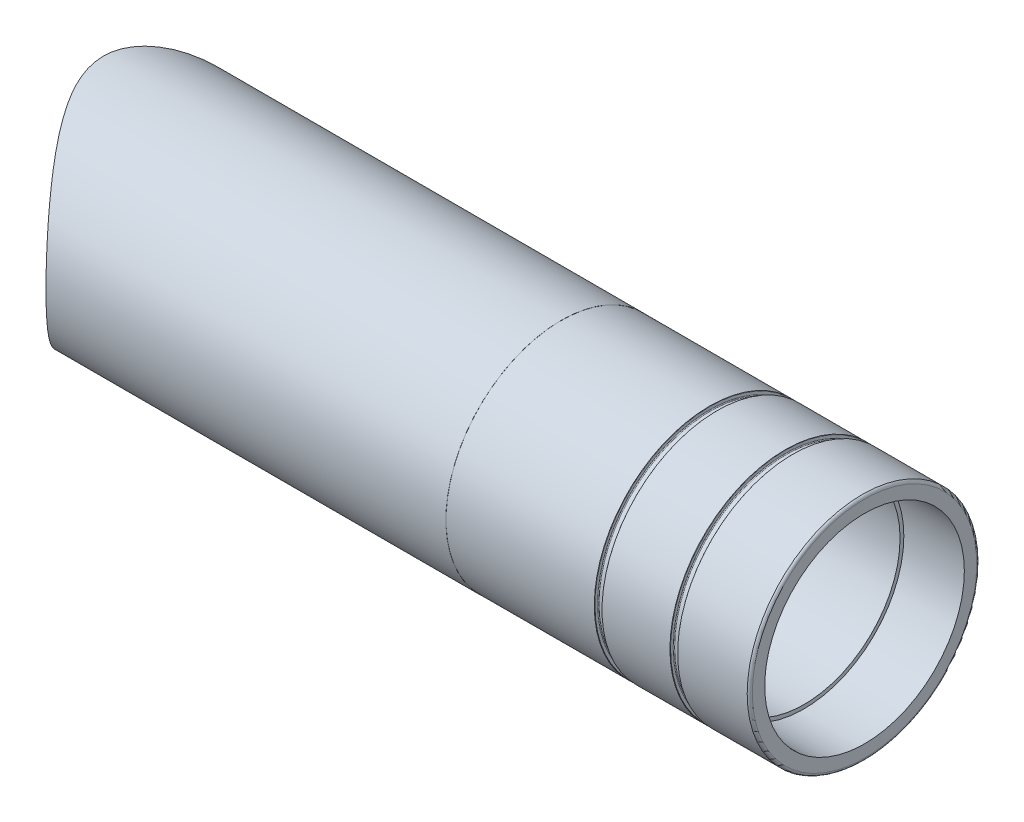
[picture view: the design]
ISO-10303-21;
HEADER;
FILE_DESCRIPTION(('STEP AP214'),'2;1');
FILE_NAME('part.step','',(''),(''),'','','');
FILE_SCHEMA(('AUTOMOTIVE_DESIGN { 1 0 10303 214 1 1 1 1 }'));
ENDSEC;
DATA;
#1=APPLICATION_CONTEXT('core data for automotive mechanical design processes');
#2=APPLICATION_PROTOCOL_DEFINITION('international standard','automotive_design',2000,#1);
#3=PRODUCT_CONTEXT('',#1,'mechanical');
#4=PRODUCT('Part','Part','',(#3));
#5=PRODUCT_RELATED_PRODUCT_CATEGORY('part','',(#4));
#6=PRODUCT_DEFINITION_FORMATION('','',#4);
#7=PRODUCT_DEFINITION_CONTEXT('part definition',#1,'design');
#8=PRODUCT_DEFINITION('design','',#6,#7);
#9=PRODUCT_DEFINITION_SHAPE('','',#8);
#10=(LENGTH_UNIT() NAMED_UNIT(*) SI_UNIT(.MILLI.,.METRE.));
#11=(NAMED_UNIT(*) PLANE_ANGLE_UNIT() SI_UNIT($,.RADIAN.));
#12=(NAMED_UNIT(*) SI_UNIT($,.STERADIAN.) SOLID_ANGLE_UNIT());
#13=UNCERTAINTY_MEASURE_WITH_UNIT(LENGTH_MEASURE(1.E-05),#10,'distance_accuracy_value','');
#14=(GEOMETRIC_REPRESENTATION_CONTEXT(3) GLOBAL_UNCERTAINTY_ASSIGNED_CONTEXT((#13)) GLOBAL_UNIT_ASSIGNED_CONTEXT((#10,
#11,#12)) REPRESENTATION_CONTEXT('',''));
#15=CARTESIAN_POINT('',(0.,0.,0.));
#16=DIRECTION('',(0.,0.,1.));
#17=DIRECTION('',(1.,0.,0.));
#18=AXIS2_PLACEMENT_3D('',#15,#16,#17);
#19=CARTESIAN_POINT('',(130.,0.,0.));
#20=DIRECTION('',(-1.,0.,0.));
#21=DIRECTION('',(0.,0.,1.));
#22=AXIS2_PLACEMENT_3D('',#19,#20,#21);
#23=CYLINDRICAL_SURFACE('',#22,38.1);
#24=CARTESIAN_POINT('',(-121.633822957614,38.1,0.));
#25=CARTESIAN_POINT('',(-121.633806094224,38.0999929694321,0.712902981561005));
#26=CARTESIAN_POINT('',(-121.606812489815,38.0799361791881,1.42607195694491));
#27=CARTESIAN_POINT('',(-121.500174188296,38.0001862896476,2.84651109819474));
#28=CARTESIAN_POINT('',(-121.420493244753,37.9404659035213,3.55377686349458));
#29=CARTESIAN_POINT('',(-121.212067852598,37.7825619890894,4.95874631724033));
#30=CARTESIAN_POINT('',(-121.083181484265,37.6842671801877,5.65641624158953));
#31=CARTESIAN_POINT('',(-120.782014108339,37.4512405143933,7.03592331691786));
#32=CARTESIAN_POINT('',(-120.609733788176,37.316509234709,7.71776071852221));
#33=CARTESIAN_POINT('',(-120.161172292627,36.9594738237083,9.29919618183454));
#34=CARTESIAN_POINT('',(-119.869608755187,36.7230293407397,10.1912740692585));
#35=CARTESIAN_POINT('',(-119.234485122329,36.1925973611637,11.9390531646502));
#36=CARTESIAN_POINT('',(-118.890901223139,35.8985835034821,12.7947374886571));
#37=CARTESIAN_POINT('',(-118.164909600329,35.2563815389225,14.4708260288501));
#38=CARTESIAN_POINT('',(-117.782415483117,34.9080719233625,15.2911457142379));
#39=CARTESIAN_POINT('',(-116.991025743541,34.1607056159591,16.8949377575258));
#40=CARTESIAN_POINT('',(-116.582130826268,33.7616502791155,17.678411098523));
#41=CARTESIAN_POINT('',(-115.879872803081,33.0489348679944,18.9666786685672));
#42=CARTESIAN_POINT('',(-115.590934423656,32.7482571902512,19.4811461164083));
#43=CARTESIAN_POINT('',(-115.007908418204,32.1245366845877,20.4933534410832));
#44=CARTESIAN_POINT('',(-114.713820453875,31.80149238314,20.9910922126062));
#45=CARTESIAN_POINT('',(-113.827347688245,30.7990943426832,22.4595525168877));
#46=CARTESIAN_POINT('',(-113.230812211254,30.0865336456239,23.4054131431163));
#47=CARTESIAN_POINT('',(-112.044403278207,28.5752646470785,25.2282523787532));
#48=CARTESIAN_POINT('',(-111.454524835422,27.7766263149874,26.105285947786));
#49=CARTESIAN_POINT('',(-110.295797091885,26.0934756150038,27.7876831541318));
#50=CARTESIAN_POINT('',(-109.726940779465,25.2089922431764,28.5930708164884));
#51=CARTESIAN_POINT('',(-108.733664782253,23.5390612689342,29.9741920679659));
#52=CARTESIAN_POINT('',(-108.302977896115,22.7687723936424,30.5637897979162));
#53=CARTESIAN_POINT('',(-107.471226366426,21.1745471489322,31.6891191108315));
#54=CARTESIAN_POINT('',(-107.070160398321,20.3506131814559,32.2248531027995));
#55=CARTESIAN_POINT('',(-106.305395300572,18.6520232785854,33.2368483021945));
#56=CARTESIAN_POINT('',(-105.941649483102,17.7774329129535,33.7131839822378));
#57=CARTESIAN_POINT('',(-105.25824077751,15.9796479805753,34.6015251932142));
#58=CARTESIAN_POINT('',(-104.938570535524,15.0564615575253,35.0135414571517));
#59=CARTESIAN_POINT('',(-104.398197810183,13.3196580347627,35.7060673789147));
#60=CARTESIAN_POINT('',(-104.169853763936,12.5125906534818,35.9970673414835));
#61=CARTESIAN_POINT('',(-103.753034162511,10.8712805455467,36.5262707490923));
#62=CARTESIAN_POINT('',(-103.564554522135,10.0370406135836,36.7644796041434));
#63=CARTESIAN_POINT('',(-103.231088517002,8.34631717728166,37.1847743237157));
#64=CARTESIAN_POINT('',(-103.086085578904,7.48984228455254,37.3668815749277));
#65=CARTESIAN_POINT('',(-102.842431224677,5.7599142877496,37.6723345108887));
#66=CARTESIAN_POINT('',(-102.743780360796,4.88646098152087,37.7956794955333));
#67=CARTESIAN_POINT('',(-102.594702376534,3.12585197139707,37.9819085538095));
#68=CARTESIAN_POINT('',(-102.544447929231,2.23865859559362,38.0445761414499));
#69=CARTESIAN_POINT('',(-102.493907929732,0.460626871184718,38.107599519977));
#70=CARTESIAN_POINT('',(-102.493622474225,-0.43021148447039,38.1079551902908));
#71=CARTESIAN_POINT('',(-102.543026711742,-2.20834915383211,38.0463486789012));
#72=CARTESIAN_POINT('',(-102.592717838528,-3.09564836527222,37.9843847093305));
#73=CARTESIAN_POINT('',(-102.740957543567,-4.85966327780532,37.7992086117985));
#74=CARTESIAN_POINT('',(-102.839504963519,-5.73637922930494,37.6759979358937));
#75=CARTESIAN_POINT('',(-103.07654079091,-7.424619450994,37.3788518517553));
#76=CARTESIAN_POINT('',(-103.21251360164,-8.23706430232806,37.2081052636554));
#77=CARTESIAN_POINT('',(-103.523617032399,-9.8419475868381,36.8161429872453));
#78=CARTESIAN_POINT('',(-103.698745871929,-10.6343869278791,36.5949295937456));
#79=CARTESIAN_POINT('',(-104.085189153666,-12.1953603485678,36.1047446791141));
#80=CARTESIAN_POINT('',(-104.296508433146,-12.963891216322,35.8357667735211));
#81=CARTESIAN_POINT('',(-104.751982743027,-14.4737297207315,35.2530295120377));
#82=CARTESIAN_POINT('',(-104.9961397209,-15.2150357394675,34.9392675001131));
#83=CARTESIAN_POINT('',(-105.538532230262,-16.7374369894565,34.2379349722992));
#84=CARTESIAN_POINT('',(-105.839706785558,-17.5155533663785,33.8461749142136));
#85=CARTESIAN_POINT('',(-106.472482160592,-19.0336982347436,33.0163123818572));
#86=CARTESIAN_POINT('',(-106.804084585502,-19.7737247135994,32.578207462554));
#87=CARTESIAN_POINT('',(-107.493074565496,-21.2143597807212,31.6589852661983));
#88=CARTESIAN_POINT('',(-107.850471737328,-21.9149534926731,31.1778519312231));
#89=CARTESIAN_POINT('',(-108.586206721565,-23.2754358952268,30.1757845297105));
#90=CARTESIAN_POINT('',(-108.964545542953,-23.9353226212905,29.6548485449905));
#91=CARTESIAN_POINT('',(-109.817239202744,-25.3457609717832,28.4643791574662));
#92=CARTESIAN_POINT('',(-110.295298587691,-26.0869274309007,27.7863627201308));
#93=CARTESIAN_POINT('',(-111.266756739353,-27.5086771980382,26.3795967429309));
#94=CARTESIAN_POINT('',(-111.760158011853,-28.1892505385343,25.6508388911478));
#95=CARTESIAN_POINT('',(-112.754109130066,-29.4900710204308,24.1440992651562));
#96=CARTESIAN_POINT('',(-113.254666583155,-30.110247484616,23.3660615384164));
#97=CARTESIAN_POINT('',(-114.252783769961,-31.2886958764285,21.762751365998));
#98=CARTESIAN_POINT('',(-114.750343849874,-31.8469750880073,20.9374844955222));
#99=CARTESIAN_POINT('',(-115.687077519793,-32.8527304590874,19.3166619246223));
#100=CARTESIAN_POINT('',(-116.127456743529,-33.3056628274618,18.5251885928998));
#101=CARTESIAN_POINT('',(-116.986986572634,-34.1578258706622,16.9024516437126));
#102=CARTESIAN_POINT('',(-117.40613444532,-34.5570496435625,16.071182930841));
#103=CARTESIAN_POINT('',(-118.210728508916,-35.2985991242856,14.3693876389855));
#104=CARTESIAN_POINT('',(-118.596220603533,-35.641002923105,13.4989170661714));
#105=CARTESIAN_POINT('',(-119.31969284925,-36.2656462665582,11.7176212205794));
#106=CARTESIAN_POINT('',(-119.657696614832,-36.5479157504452,10.8068163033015));
#107=CARTESIAN_POINT('',(-120.179430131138,-36.9737950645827,9.22012161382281));
#108=CARTESIAN_POINT('',(-120.379297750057,-37.1337707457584,8.55391338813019));
#109=CARTESIAN_POINT('',(-120.74063606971,-37.4191487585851,7.20369408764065));
#110=CARTESIAN_POINT('',(-120.902105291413,-37.5445497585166,6.51968232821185));
#111=CARTESIAN_POINT('',(-121.179950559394,-37.7582506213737,5.13914523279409));
#112=CARTESIAN_POINT('',(-121.296471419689,-37.8466697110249,4.44266777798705));
#113=CARTESIAN_POINT('',(-121.479882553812,-37.9850804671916,3.03968919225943));
#114=CARTESIAN_POINT('',(-121.546807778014,-38.0350991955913,2.33319547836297));
#115=CARTESIAN_POINT('',(-121.602801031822,-38.0768870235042,1.35427329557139));
#116=CARTESIAN_POINT('',(-121.614421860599,-38.0855491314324,1.0836525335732));
#117=CARTESIAN_POINT('',(-121.629936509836,-38.0971073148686,0.542034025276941));
#118=CARTESIAN_POINT('',(-121.63382936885,-38.1000026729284,0.271036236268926));
#119=CARTESIAN_POINT('',(-121.633806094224,-38.0999929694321,-0.712902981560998));
#120=CARTESIAN_POINT('',(-121.606812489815,-38.0799361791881,-1.4260719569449));
#121=CARTESIAN_POINT('',(-121.500174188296,-38.0001862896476,-2.84651109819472));
#122=CARTESIAN_POINT('',(-121.420493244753,-37.9404659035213,-3.55377686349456));
#123=CARTESIAN_POINT('',(-121.212067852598,-37.7825619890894,-4.95874631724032));
#124=CARTESIAN_POINT('',(-121.083181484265,-37.6842671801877,-5.65641624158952));
#125=CARTESIAN_POINT('',(-120.782014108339,-37.4512405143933,-7.03592331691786));
#126=CARTESIAN_POINT('',(-120.609733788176,-37.316509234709,-7.7177607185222));
#127=CARTESIAN_POINT('',(-120.161172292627,-36.9594738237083,-9.29919618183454));
#128=CARTESIAN_POINT('',(-119.869608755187,-36.7230293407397,-10.1912740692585));
#129=CARTESIAN_POINT('',(-119.234485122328,-36.1925973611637,-11.9390531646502));
#130=CARTESIAN_POINT('',(-118.890901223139,-35.8985835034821,-12.7947374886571));
#131=CARTESIAN_POINT('',(-118.164909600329,-35.2563815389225,-14.4708260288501));
#132=CARTESIAN_POINT('',(-117.782415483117,-34.9080719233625,-15.2911457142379));
#133=CARTESIAN_POINT('',(-116.991025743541,-34.1607056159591,-16.8949377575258));
#134=CARTESIAN_POINT('',(-116.582130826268,-33.7616502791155,-17.678411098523));
#135=CARTESIAN_POINT('',(-115.879872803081,-33.0489348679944,-18.9666786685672));
#136=CARTESIAN_POINT('',(-115.590934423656,-32.7482571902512,-19.4811461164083));
#137=CARTESIAN_POINT('',(-115.007908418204,-32.1245366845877,-20.4933534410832));
#138=CARTESIAN_POINT('',(-114.713820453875,-31.80149238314,-20.9910922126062));
#139=CARTESIAN_POINT('',(-113.827347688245,-30.7990943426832,-22.4595525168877));
#140=CARTESIAN_POINT('',(-113.230812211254,-30.0865336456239,-23.4054131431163));
#141=CARTESIAN_POINT('',(-112.044403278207,-28.5752646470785,-25.2282523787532));
#142=CARTESIAN_POINT('',(-111.454524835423,-27.7766263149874,-26.105285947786));
#143=CARTESIAN_POINT('',(-110.295797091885,-26.0934756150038,-27.7876831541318));
#144=CARTESIAN_POINT('',(-109.726940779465,-25.2089922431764,-28.5930708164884));
#145=CARTESIAN_POINT('',(-108.733664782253,-23.5390612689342,-29.9741920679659));
#146=CARTESIAN_POINT('',(-108.302977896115,-22.7687723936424,-30.5637897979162));
#147=CARTESIAN_POINT('',(-107.471226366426,-21.1745471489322,-31.6891191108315));
#148=CARTESIAN_POINT('',(-107.070160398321,-20.3506131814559,-32.2248531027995));
#149=CARTESIAN_POINT('',(-106.305395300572,-18.6520232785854,-33.2368483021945));
#150=CARTESIAN_POINT('',(-105.941649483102,-17.7774329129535,-33.7131839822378));
#151=CARTESIAN_POINT('',(-105.25824077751,-15.9796479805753,-34.6015251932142));
#152=CARTESIAN_POINT('',(-104.938570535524,-15.0564615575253,-35.0135414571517));
#153=CARTESIAN_POINT('',(-104.398197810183,-13.3196580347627,-35.7060673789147));
#154=CARTESIAN_POINT('',(-104.169853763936,-12.5125906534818,-35.9970673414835));
#155=CARTESIAN_POINT('',(-103.753034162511,-10.8712805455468,-36.5262707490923));
#156=CARTESIAN_POINT('',(-103.564554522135,-10.0370406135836,-36.7644796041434));
#157=CARTESIAN_POINT('',(-103.231088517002,-8.34631717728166,-37.1847743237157));
#158=CARTESIAN_POINT('',(-103.086085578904,-7.48984228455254,-37.3668815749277));
#159=CARTESIAN_POINT('',(-102.842431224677,-5.7599142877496,-37.6723345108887));
#160=CARTESIAN_POINT('',(-102.743780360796,-4.88646098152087,-37.7956794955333));
#161=CARTESIAN_POINT('',(-102.594702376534,-3.12585197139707,-37.9819085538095));
#162=CARTESIAN_POINT('',(-102.544447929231,-2.23865859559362,-38.0445761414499));
#163=CARTESIAN_POINT('',(-102.493907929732,-0.460626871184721,-38.107599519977));
#164=CARTESIAN_POINT('',(-102.493622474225,0.430211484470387,-38.1079551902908));
#165=CARTESIAN_POINT('',(-102.543026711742,2.20834915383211,-38.0463486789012));
#166=CARTESIAN_POINT('',(-102.592717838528,3.09564836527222,-37.9843847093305));
#167=CARTESIAN_POINT('',(-102.740957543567,4.85966327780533,-37.7992086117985));
#168=CARTESIAN_POINT('',(-102.839504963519,5.73637922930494,-37.6759979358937));
#169=CARTESIAN_POINT('',(-103.07654079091,7.42461945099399,-37.3788518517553));
#170=CARTESIAN_POINT('',(-103.21251360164,8.23706430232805,-37.2081052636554));
#171=CARTESIAN_POINT('',(-103.523617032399,9.84194758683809,-36.8161429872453));
#172=CARTESIAN_POINT('',(-103.698745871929,10.6343869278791,-36.5949295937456));
#173=CARTESIAN_POINT('',(-104.085189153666,12.1953603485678,-36.1047446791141));
#174=CARTESIAN_POINT('',(-104.296508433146,12.963891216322,-35.8357667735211));
#175=CARTESIAN_POINT('',(-104.751982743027,14.4737297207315,-35.2530295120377));
#176=CARTESIAN_POINT('',(-104.9961397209,15.2150357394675,-34.9392675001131));
#177=CARTESIAN_POINT('',(-105.538532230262,16.7374369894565,-34.2379349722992));
#178=CARTESIAN_POINT('',(-105.839706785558,17.5155533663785,-33.8461749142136));
#179=CARTESIAN_POINT('',(-106.472482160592,19.0336982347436,-33.0163123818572));
#180=CARTESIAN_POINT('',(-106.804084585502,19.7737247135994,-32.578207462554));
#181=CARTESIAN_POINT('',(-107.493074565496,21.2143597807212,-31.6589852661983));
#182=CARTESIAN_POINT('',(-107.850471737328,21.9149534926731,-31.177851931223));
#183=CARTESIAN_POINT('',(-108.586206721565,23.2754358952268,-30.1757845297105));
#184=CARTESIAN_POINT('',(-108.964545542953,23.9353226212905,-29.6548485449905));
#185=CARTESIAN_POINT('',(-109.817239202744,25.3457609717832,-28.4643791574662));
#186=CARTESIAN_POINT('',(-110.295298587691,26.0869274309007,-27.7863627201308));
#187=CARTESIAN_POINT('',(-111.266756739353,27.5086771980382,-26.3795967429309));
#188=CARTESIAN_POINT('',(-111.760158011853,28.1892505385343,-25.6508388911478));
#189=CARTESIAN_POINT('',(-112.754109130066,29.4900710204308,-24.1440992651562));
#190=CARTESIAN_POINT('',(-113.254666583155,30.110247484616,-23.3660615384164));
#191=CARTESIAN_POINT('',(-114.252783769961,31.2886958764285,-21.762751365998));
#192=CARTESIAN_POINT('',(-114.750343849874,31.8469750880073,-20.9374844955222));
#193=CARTESIAN_POINT('',(-115.687077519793,32.8527304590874,-19.3166619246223));
#194=CARTESIAN_POINT('',(-116.127456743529,33.3056628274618,-18.5251885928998));
#195=CARTESIAN_POINT('',(-116.986986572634,34.1578258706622,-16.9024516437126));
#196=CARTESIAN_POINT('',(-117.40613444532,34.5570496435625,-16.071182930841));
#197=CARTESIAN_POINT('',(-118.210728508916,35.2985991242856,-14.3693876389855));
#198=CARTESIAN_POINT('',(-118.596220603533,35.641002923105,-13.4989170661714));
#199=CARTESIAN_POINT('',(-119.31969284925,36.2656462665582,-11.7176212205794));
#200=CARTESIAN_POINT('',(-119.657696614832,36.5479157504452,-10.8068163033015));
#201=CARTESIAN_POINT('',(-120.179430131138,36.9737950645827,-9.22012161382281));
#202=CARTESIAN_POINT('',(-120.379297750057,37.1337707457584,-8.55391338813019));
#203=CARTESIAN_POINT('',(-120.74063606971,37.4191487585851,-7.20369408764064));
#204=CARTESIAN_POINT('',(-120.902105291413,37.5445497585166,-6.51968232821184));
#205=CARTESIAN_POINT('',(-121.179950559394,37.7582506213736,-5.13914523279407));
#206=CARTESIAN_POINT('',(-121.296471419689,37.8466697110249,-4.44266777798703));
#207=CARTESIAN_POINT('',(-121.479882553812,37.9850804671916,-3.03968919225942));
#208=CARTESIAN_POINT('',(-121.546807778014,38.0350991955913,-2.33319547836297));
#209=CARTESIAN_POINT('',(-121.602801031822,38.0768870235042,-1.35427329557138));
#210=CARTESIAN_POINT('',(-121.614421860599,38.0855491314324,-1.08365253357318));
#211=CARTESIAN_POINT('',(-121.629936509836,38.0971073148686,-0.542034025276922));
#212=CARTESIAN_POINT('',(-121.63382936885,38.1000026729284,-0.271036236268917));
#213=CARTESIAN_POINT('',(-121.633822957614,38.1,0.));
#214=B_SPLINE_CURVE_WITH_KNOTS('',3,(#24,#25,#26,#27,#28,#29,#30,#31,#32,#33,#34,#35,#36,#37,
#38,#39,#40,#41,#42,#43,#44,#45,#46,#47,#48,#49,#50,#51,#52,#53,#54,#55,#56,#57,#58,#59,#60,#61,
#62,#63,#64,#65,#66,#67,#68,#69,#70,#71,#72,#73,#74,#75,#76,#77,#78,#79,#80,#81,#82,#83,#84,#85,
#86,#87,#88,#89,#90,#91,#92,#93,#94,#95,#96,#97,#98,#99,#100,#101,#102,#103,#104,#105,#106,#107,
#108,#109,#110,#111,#112,#113,#114,#115,#116,#117,#118,#119,#120,#121,#122,#123,#124,#125,#126,
#127,#128,#129,#130,#131,#132,#133,#134,#135,#136,#137,#138,#139,#140,#141,#142,#143,#144,#145,
#146,#147,#148,#149,#150,#151,#152,#153,#154,#155,#156,#157,#158,#159,#160,#161,#162,#163,#164,
#165,#166,#167,#168,#169,#170,#171,#172,#173,#174,#175,#176,#177,#178,#179,#180,#181,#182,#183,
#184,#185,#186,#187,#188,#189,#190,#191,#192,#193,#194,#195,#196,#197,#198,#199,#200,#201,#202,
#203,#204,#205,#206,#207,#208,#209,#210,#211,#212,#213),.UNSPECIFIED.,.T.,.F.,(4,2,2,2,2,2,2,2,
2,2,2,2,2,2,2,2,2,2,2,2,2,2,2,2,2,2,2,2,2,2,2,2,2,2,2,2,2,2,2,2,2,2,2,2,2,2,2,2,2,2,2,2,2,2,2,2,
2,2,2,2,2,2,2,2,2,2,2,2,2,2,2,2,2,2,2,2,2,2,2,2,2,2,2,2,2,2,2,2,2,2,2,2,2,2,4),(0.,
2.13839611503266,4.27826487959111,6.42435272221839,8.57040656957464,11.4693230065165,
14.3695699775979,17.2764031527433,20.1831587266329,22.1693054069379,24.1555830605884,
28.1285370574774,32.0982855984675,36.0666979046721,39.2479049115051,42.4289695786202,
45.6060048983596,48.7825094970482,51.443218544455,54.1036547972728,56.7630755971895,
59.4225280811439,62.091434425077,64.7603459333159,67.4293340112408,70.0982588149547,
72.6193037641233,75.1402340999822,77.6615016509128,80.1829187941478,82.9455722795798,
85.7083715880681,88.4722062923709,91.2361742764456,94.5704212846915,97.9052157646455,
101.243866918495,104.582124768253,107.617933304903,110.654131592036,113.686121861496,
116.716599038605,118.855911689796,120.995306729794,123.127750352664,125.258689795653,
126.071578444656,126.884568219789,129.022964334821,131.16283309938,133.308920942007,
135.454974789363,138.353891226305,141.254138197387,144.160971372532,147.067726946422,
149.053873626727,151.040151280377,155.013105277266,158.982853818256,162.951266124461,
166.132473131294,169.313537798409,172.490573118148,175.667077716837,178.327786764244,
180.988223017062,183.647643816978,186.307096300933,188.976002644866,191.644914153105,
194.313902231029,196.982827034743,199.503871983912,202.024802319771,204.546069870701,
207.067487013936,209.830140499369,212.592939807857,215.35677451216,218.120742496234,
221.45498950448,224.789783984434,228.128435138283,231.466692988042,234.502501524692,
237.538699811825,240.570690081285,243.601167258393,245.740479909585,247.879874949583,
250.012318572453,252.143258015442,252.956146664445,253.769136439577),.UNSPECIFIED.);
#215=CARTESIAN_POINT('',(-121.633822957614,38.1,0.));
#216=VERTEX_POINT('',#215);
#217=EDGE_CURVE('E116',#216,#216,#214,.T.);
#218=ORIENTED_EDGE('',*,*,#217,.T.);
#219=EDGE_LOOP('',(#218));
#220=FACE_BOUND('',#219,.T.);
#221=CARTESIAN_POINT('',(29.7,0.,0.));
#222=DIRECTION('',(1.,0.,0.));
#223=DIRECTION('',(0.,0.,-1.));
#224=AXIS2_PLACEMENT_3D('',#221,#222,#223);
#225=CIRCLE('',#224,38.1);
#226=CARTESIAN_POINT('',(29.7,0.,-38.1));
#227=VERTEX_POINT('',#226);
#228=EDGE_CURVE('E35',#227,#227,#225,.T.);
#229=ORIENTED_EDGE('',*,*,#228,.F.);
#230=EDGE_LOOP('',(#229));
#231=FACE_BOUND('',#230,.T.);
#232=ADVANCED_FACE('F31',(#220,#231),#23,.T.);
#233=CARTESIAN_POINT('',(129.,0.,0.));
#234=DIRECTION('',(1.,0.,0.));
#235=DIRECTION('',(0.,0.,-1.));
#236=AXIS2_PLACEMENT_3D('',#233,#234,#235);
#237=TOROIDAL_SURFACE('',#236,37.1,1.);
#238=CARTESIAN_POINT('',(130.,0.,0.));
#239=DIRECTION('',(1.,0.,0.));
#240=DIRECTION('',(0.,0.,-1.));
#241=AXIS2_PLACEMENT_3D('',#238,#239,#240);
#242=CIRCLE('',#241,37.1);
#243=CARTESIAN_POINT('',(130.,0.,-37.1));
#244=VERTEX_POINT('',#243);
#245=EDGE_CURVE('E122',#244,#244,#242,.T.);
#246=ORIENTED_EDGE('',*,*,#245,.F.);
#247=EDGE_LOOP('',(#246));
#248=FACE_BOUND('',#247,.T.);
#249=CARTESIAN_POINT('',(129.274804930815,0.,0.));
#250=DIRECTION('',(-1.,0.,0.));
#251=DIRECTION('',(0.,0.,1.));
#252=AXIS2_PLACEMENT_3D('',#249,#250,#251);
#253=CIRCLE('',#252,38.0615);
#254=CARTESIAN_POINT('',(129.274804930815,0.,38.0615));
#255=VERTEX_POINT('',#254);
#256=EDGE_CURVE('E144',#255,#255,#253,.F.);
#257=ORIENTED_EDGE('',*,*,#256,.T.);
#258=EDGE_LOOP('',(#257));
#259=FACE_BOUND('',#258,.T.);
#260=ADVANCED_FACE('F207',(#248,#259),#237,.T.);
#261=CARTESIAN_POINT('',(130.,0.,0.));
#262=DIRECTION('',(-1.,0.,0.));
#263=DIRECTION('',(0.,0.,1.));
#264=AXIS2_PLACEMENT_3D('',#261,#262,#263);
#265=CYLINDRICAL_SURFACE('',#264,31.75);
#266=CARTESIAN_POINT('',(-80.,0.,0.));
#267=DIRECTION('',(1.,0.,0.));
#268=DIRECTION('',(0.,0.,-1.));
#269=AXIS2_PLACEMENT_3D('',#266,#267,#268);
#270=CIRCLE('',#269,31.75);
#271=CARTESIAN_POINT('',(-80.,0.,-31.75));
#272=VERTEX_POINT('',#271);
#273=EDGE_CURVE('E55',#272,#272,#270,.T.);
#274=ORIENTED_EDGE('',*,*,#273,.F.);
#275=EDGE_LOOP('',(#274));
#276=FACE_BOUND('',#275,.T.);
#277=CARTESIAN_POINT('',(110.,0.,0.));
#278=DIRECTION('',(1.,0.,0.));
#279=DIRECTION('',(0.,0.,-1.));
#280=AXIS2_PLACEMENT_3D('',#277,#278,#279);
#281=CIRCLE('',#280,31.75);
#282=CARTESIAN_POINT('',(110.,0.,-31.75));
#283=VERTEX_POINT('',#282);
#284=EDGE_CURVE('E156',#283,#283,#281,.T.);
#285=ORIENTED_EDGE('',*,*,#284,.T.);
#286=EDGE_LOOP('',(#285));
#287=FACE_BOUND('',#286,.T.);
#288=ADVANCED_FACE('F204',(#276,#287),#265,.F.);
#289=CARTESIAN_POINT('',(-150.,0.,38.101));
#290=DIRECTION('',(0.,0.,-1.));
#291=DIRECTION('',(-1.,0.,0.));
#292=AXIS2_PLACEMENT_3D('',#289,#290,#291);
#293=CYLINDRICAL_SURFACE('',#292,47.5);
#294=ORIENTED_EDGE('',*,*,#217,.F.);
#295=EDGE_LOOP('',(#294));
#296=FACE_BOUND('',#295,.T.);
#297=CARTESIAN_POINT('',(-102.5,0.,33.));
#298=CARTESIAN_POINT('',(-102.49999794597,-0.821813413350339,33.0000022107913));
#299=CARTESIAN_POINT('',(-102.521371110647,-1.64360020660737,32.9692605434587));
#300=CARTESIAN_POINT('',(-102.606322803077,-3.2803756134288,32.8468048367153));
#301=CARTESIAN_POINT('',(-102.669899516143,-4.09536451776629,32.7550934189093));
#302=CARTESIAN_POINT('',(-102.837729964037,-5.71238311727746,32.5121118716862));
#303=CARTESIAN_POINT('',(-102.941996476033,-6.51440865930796,32.3608230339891));
#304=CARTESIAN_POINT('',(-103.188759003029,-8.09945233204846,32.0009285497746));
#305=CARTESIAN_POINT('',(-103.33125594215,-8.88247000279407,31.7923215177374));
#306=CARTESIAN_POINT('',(-103.65052470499,-10.4206614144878,31.3217746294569));
#307=CARTESIAN_POINT('',(-103.827123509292,-11.17595372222,31.0601036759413));
#308=CARTESIAN_POINT('',(-104.211418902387,-12.6586916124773,30.485892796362));
#309=CARTESIAN_POINT('',(-104.419115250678,-13.3861374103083,30.1733532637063));
#310=CARTESIAN_POINT('',(-104.861652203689,-14.8099766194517,29.5005870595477));
#311=CARTESIAN_POINT('',(-105.096492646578,-15.5063702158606,29.1403606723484));
#312=CARTESIAN_POINT('',(-105.589169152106,-16.8656700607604,28.3752981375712));
#313=CARTESIAN_POINT('',(-105.847006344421,-17.5285746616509,27.9704597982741));
#314=CARTESIAN_POINT('',(-106.404867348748,-18.8756844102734,27.081647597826));
#315=CARTESIAN_POINT('',(-106.706607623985,-19.5566527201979,26.5938467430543));
#316=CARTESIAN_POINT('',(-107.326633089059,-20.8749722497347,25.5720779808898));
#317=CARTESIAN_POINT('',(-107.644919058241,-21.5123214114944,25.0381078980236));
#318=CARTESIAN_POINT('',(-108.292733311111,-22.7428671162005,23.9259430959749));
#319=CARTESIAN_POINT('',(-108.622276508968,-23.3360014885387,23.3476883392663));
#320=CARTESIAN_POINT('',(-109.286198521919,-24.4759376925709,22.1497673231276));
#321=CARTESIAN_POINT('',(-109.620577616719,-25.0227368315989,21.5300986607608));
#322=CARTESIAN_POINT('',(-110.345688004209,-26.1594166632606,20.1401268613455));
#323=CARTESIAN_POINT('',(-110.736143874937,-26.7403441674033,19.3623280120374));
#324=CARTESIAN_POINT('',(-111.503902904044,-27.8342806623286,17.7538453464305));
#325=CARTESIAN_POINT('',(-111.881202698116,-28.3472723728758,16.9231481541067));
#326=CARTESIAN_POINT('',(-112.60946561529,-29.3011519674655,15.2118665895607));
#327=CARTESIAN_POINT('',(-112.96046277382,-29.7421339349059,14.3313493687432));
#328=CARTESIAN_POINT('',(-113.622268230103,-30.5480361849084,12.5218699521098));
#329=CARTESIAN_POINT('',(-113.933097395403,-30.9129960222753,11.5929332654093));
#330=CARTESIAN_POINT('',(-114.411645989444,-31.4612104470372,9.98376961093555));
#331=CARTESIAN_POINT('',(-114.593952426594,-31.6658048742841,9.31509140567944));
#332=CARTESIAN_POINT('',(-114.926401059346,-32.0336411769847,7.95860457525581));
#333=CARTESIAN_POINT('',(-115.076548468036,-32.1968897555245,7.2707990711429));
#334=CARTESIAN_POINT('',(-115.339312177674,-32.4795939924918,5.88033972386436));
#335=CARTESIAN_POINT('',(-115.451990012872,-32.5991214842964,5.17771226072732));
#336=CARTESIAN_POINT('',(-115.635771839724,-32.7928002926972,3.76077566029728));
#337=CARTESIAN_POINT('',(-115.70687587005,-32.866951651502,3.04646653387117));
#338=CARTESIAN_POINT('',(-115.804736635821,-32.9687588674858,1.60748183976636));
#339=CARTESIAN_POINT('',(-115.831245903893,-32.9961552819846,0.882770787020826));
#340=CARTESIAN_POINT('',(-115.837943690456,-33.0030897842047,-0.567095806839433));
#341=CARTESIAN_POINT('',(-115.818132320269,-32.9826279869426,-1.29225134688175));
#342=CARTESIAN_POINT('',(-115.733069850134,-32.8942425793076,-2.73737948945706));
#343=CARTESIAN_POINT('',(-115.667791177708,-32.8262901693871,-3.45734867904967));
#344=CARTESIAN_POINT('',(-115.494614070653,-32.6442035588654,-4.88617881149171));
#345=CARTESIAN_POINT('',(-115.386714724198,-32.53006837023,-5.59503951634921));
#346=CARTESIAN_POINT('',(-115.140600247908,-32.2661212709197,-6.95309951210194));
#347=CARTESIAN_POINT('',(-115.004711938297,-32.1189970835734,-7.60325161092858));
#348=CARTESIAN_POINT('',(-114.703486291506,-31.7876739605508,-8.88727282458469));
#349=CARTESIAN_POINT('',(-114.538138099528,-31.6034613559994,-9.52113583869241));
#350=CARTESIAN_POINT('',(-114.182431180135,-31.1997452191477,-10.7706665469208));
#351=CARTESIAN_POINT('',(-113.992059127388,-30.9802228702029,-11.3863243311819));
#352=CARTESIAN_POINT('',(-113.590892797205,-30.5077527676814,-12.5976047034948));
#353=CARTESIAN_POINT('',(-113.380101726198,-30.2548102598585,-13.1932304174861));
#354=CARTESIAN_POINT('',(-112.828522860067,-29.5771639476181,-14.6679780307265));
#355=CARTESIAN_POINT('',(-112.47710340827,-29.1315079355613,-15.5335784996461));
#356=CARTESIAN_POINT('',(-111.750456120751,-28.170649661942,-17.2148983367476));
#357=CARTESIAN_POINT('',(-111.375218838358,-27.6554197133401,-18.0305976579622));
#358=CARTESIAN_POINT('',(-110.612353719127,-26.5576890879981,-19.6116503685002));
#359=CARTESIAN_POINT('',(-110.224705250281,-25.9750716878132,-20.3769126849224));
#360=CARTESIAN_POINT('',(-109.448475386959,-24.745753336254,-21.8533834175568));
#361=CARTESIAN_POINT('',(-109.059894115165,-24.0990604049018,-22.5645985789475));
#362=CARTESIAN_POINT('',(-108.287330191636,-22.7359558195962,-23.9378891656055));
#363=CARTESIAN_POINT('',(-107.903445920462,-22.0188522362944,-24.5993341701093));
#364=CARTESIAN_POINT('',(-107.154269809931,-20.5229900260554,-25.8604682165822));
#365=CARTESIAN_POINT('',(-106.788979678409,-19.7442257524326,-26.4601515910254));
#366=CARTESIAN_POINT('',(-106.08691732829,-18.1291247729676,-27.5917616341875));
#367=CARTESIAN_POINT('',(-105.750094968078,-17.2928942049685,-28.123808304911));
#368=CARTESIAN_POINT('',(-105.113288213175,-15.5653398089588,-29.1154829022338));
#369=CARTESIAN_POINT('',(-104.813292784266,-14.6740326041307,-29.5751325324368));
#370=CARTESIAN_POINT('',(-104.320219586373,-13.0446646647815,-30.3224765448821));
#371=CARTESIAN_POINT('',(-104.118179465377,-12.3164029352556,-30.625705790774));
#372=CARTESIAN_POINT('',(-103.745467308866,-10.8329472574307,-31.1813131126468));
#373=CARTESIAN_POINT('',(-103.574790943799,-10.077757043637,-31.43369820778));
#374=CARTESIAN_POINT('',(-103.26837063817,-8.54490271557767,-31.884518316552));
#375=CARTESIAN_POINT('',(-103.132609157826,-7.76725010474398,-32.0829804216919));
#376=CARTESIAN_POINT('',(-102.898872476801,-6.19403766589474,-32.4234723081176));
#377=CARTESIAN_POINT('',(-102.800898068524,-5.39847746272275,-32.5655009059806));
#378=CARTESIAN_POINT('',(-102.644703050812,-3.7920427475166,-32.7914753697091));
#379=CARTESIAN_POINT('',(-102.586639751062,-2.98112043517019,-32.8751914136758));
#380=CARTESIAN_POINT('',(-102.512295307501,-1.35337757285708,-32.9823224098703));
#381=CARTESIAN_POINT('',(-102.496014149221,-0.536557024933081,-33.0057373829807));
#382=CARTESIAN_POINT('',(-102.505634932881,1.09630954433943,-32.9918889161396));
#383=CARTESIAN_POINT('',(-102.531536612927,1.91235557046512,-32.9546258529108));
#384=CARTESIAN_POINT('',(-102.624886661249,3.53704383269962,-32.8200200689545));
#385=CARTESIAN_POINT('',(-102.692333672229,4.34568630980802,-32.7226793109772));
#386=CARTESIAN_POINT('',(-102.861708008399,5.89948023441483,-32.4773136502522));
#387=CARTESIAN_POINT('',(-102.961233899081,6.64545592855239,-32.3328117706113));
#388=CARTESIAN_POINT('',(-103.193362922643,8.12073187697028,-31.9941631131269));
#389=CARTESIAN_POINT('',(-103.325964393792,8.85003296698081,-31.8000188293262));
#390=CARTESIAN_POINT('',(-103.621708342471,10.2880022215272,-31.3643351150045));
#391=CARTESIAN_POINT('',(-103.784853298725,10.9966687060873,-31.1227918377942));
#392=CARTESIAN_POINT('',(-104.138736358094,12.3899654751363,-30.5948340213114));
#393=CARTESIAN_POINT('',(-104.329475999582,13.0745944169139,-30.3084169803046));
#394=CARTESIAN_POINT('',(-104.750248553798,14.4663961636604,-29.6707192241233));
#395=CARTESIAN_POINT('',(-104.982138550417,15.1715312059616,-29.3162194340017));
#396=CARTESIAN_POINT('',(-105.469822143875,16.5483152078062,-28.5616808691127));
#397=CARTESIAN_POINT('',(-105.725616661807,17.2199628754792,-28.1616403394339));
#398=CARTESIAN_POINT('',(-106.256922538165,18.5281362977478,-27.3187472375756));
#399=CARTESIAN_POINT('',(-106.532443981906,19.1646437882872,-26.8758727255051));
#400=CARTESIAN_POINT('',(-107.098672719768,20.4006945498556,-25.9501057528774));
#401=CARTESIAN_POINT('',(-107.3893808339,21.0002358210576,-25.4672111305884));
#402=CARTESIAN_POINT('',(-108.031933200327,22.2601173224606,-24.378139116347));
#403=CARTESIAN_POINT('',(-108.385756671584,22.9134194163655,-23.76497284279));
#404=CARTESIAN_POINT('',(-109.100601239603,24.1662882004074,-22.4897688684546));
#405=CARTESIAN_POINT('',(-109.46162338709,24.7658469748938,-21.827723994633));
#406=CARTESIAN_POINT('',(-110.183167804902,25.9099896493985,-20.45654711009));
#407=CARTESIAN_POINT('',(-110.543689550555,26.45453489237,-19.7473825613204));
#408=CARTESIAN_POINT('',(-111.255335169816,27.4862424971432,-18.2840851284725));
#409=CARTESIAN_POINT('',(-111.606460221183,27.9734120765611,-17.5299579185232));
#410=CARTESIAN_POINT('',(-112.25265091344,28.8382843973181,-16.0623137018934));
#411=CARTESIAN_POINT('',(-112.549664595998,29.2221293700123,-15.3532735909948));
#412=CARTESIAN_POINT('',(-113.121059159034,29.9400096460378,-13.9014919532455));
#413=CARTESIAN_POINT('',(-113.395439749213,30.2740443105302,-13.1587499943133));
#414=CARTESIAN_POINT('',(-113.912770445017,30.8888831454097,-11.6423851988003));
#415=CARTESIAN_POINT('',(-114.155770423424,31.1697721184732,-10.8688139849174));
#416=CARTESIAN_POINT('',(-114.601875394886,31.6754899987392,-9.29236231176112));
#417=CARTESIAN_POINT('',(-114.804990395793,31.9003329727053,-8.48948926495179));
#418=CARTESIAN_POINT('',(-115.12808360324,32.2528310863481,-7.01526403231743));
#419=CARTESIAN_POINT('',(-115.256535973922,32.3908566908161,-6.34824088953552));
#420=CARTESIAN_POINT('',(-115.477255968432,32.626005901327,-5.00110176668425));
#421=CARTESIAN_POINT('',(-115.56952812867,32.7231346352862,-4.32098743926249));
#422=CARTESIAN_POINT('',(-115.714363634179,32.8748567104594,-2.95249398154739));
#423=CARTESIAN_POINT('',(-115.766966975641,32.9294928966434,-2.26412388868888));
#424=CARTESIAN_POINT('',(-115.83049922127,32.9954141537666,-0.883356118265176));
#425=CARTESIAN_POINT('',(-115.841427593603,33.0066986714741,-0.190958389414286));
#426=CARTESIAN_POINT('',(-115.821143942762,32.9856938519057,1.19302090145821));
#427=CARTESIAN_POINT('',(-115.789903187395,32.9533748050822,1.88460158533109));
#428=CARTESIAN_POINT('',(-115.686523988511,32.8457130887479,3.26127368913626));
#429=CARTESIAN_POINT('',(-115.614385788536,32.7703706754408,3.94636514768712));
#430=CARTESIAN_POINT('',(-115.431919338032,32.5778348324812,5.30631218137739));
#431=CARTESIAN_POINT('',(-115.321543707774,32.460589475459,5.98115396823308));
#432=CARTESIAN_POINT('',(-115.066567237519,32.1860260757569,7.31602986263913));
#433=CARTESIAN_POINT('',(-114.921961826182,32.0287026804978,7.97606197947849));
#434=CARTESIAN_POINT('',(-114.556260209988,31.6241345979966,9.46972435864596));
#435=CARTESIAN_POINT('',(-114.325170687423,31.3640502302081,10.2974466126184));
#436=CARTESIAN_POINT('',(-113.823672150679,30.7842499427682,11.9194115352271));
#437=CARTESIAN_POINT('',(-113.553250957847,30.4645155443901,12.7136437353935));
#438=CARTESIAN_POINT('',(-112.982756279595,29.7687125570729,14.2670573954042));
#439=CARTESIAN_POINT('',(-112.68264833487,29.3925782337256,15.0261965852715));
#440=CARTESIAN_POINT('',(-112.06219402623,28.5872566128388,16.5069407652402));
#441=CARTESIAN_POINT('',(-111.741848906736,28.1580725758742,17.2285480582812));
#442=CARTESIAN_POINT('',(-111.08160085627,27.2385000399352,18.649301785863));
#443=CARTESIAN_POINT('',(-110.741418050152,26.746935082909,19.3475555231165));
#444=CARTESIAN_POINT('',(-110.056283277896,25.7125338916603,20.7024646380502));
#445=CARTESIAN_POINT('',(-109.711331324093,25.1696977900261,21.359120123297));
#446=CARTESIAN_POINT('',(-109.023721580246,24.0340457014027,22.6294195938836));
#447=CARTESIAN_POINT('',(-108.681064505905,23.441214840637,23.2430506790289));
#448=CARTESIAN_POINT('',(-108.00483422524,22.2070110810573,24.4249623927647));
#449=CARTESIAN_POINT('',(-107.67126191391,21.5656334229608,24.9932385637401));
#450=CARTESIAN_POINT('',(-106.964663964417,20.1235779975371,26.173455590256));
#451=CARTESIAN_POINT('',(-106.594466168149,19.3142721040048,26.7766094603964));
#452=CARTESIAN_POINT('',(-105.885146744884,17.6340951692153,27.9117636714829));
#453=CARTESIAN_POINT('',(-105.546029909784,16.7632146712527,28.4437530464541));
#454=CARTESIAN_POINT('',(-104.908954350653,14.9651662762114,29.4294691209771));
#455=CARTESIAN_POINT('',(-104.6109506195,14.0380615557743,29.8832815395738));
#456=CARTESIAN_POINT('',(-104.065019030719,12.1329430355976,30.7061442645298));
#457=CARTESIAN_POINT('',(-103.817074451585,11.154946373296,31.0752228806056));
#458=CARTESIAN_POINT('',(-103.421590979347,9.34805189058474,31.65967460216));
#459=CARTESIAN_POINT('',(-103.263916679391,8.52648376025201,31.8909482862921));
#460=CARTESIAN_POINT('',(-102.990590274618,6.86125595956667,32.2901818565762));
#461=CARTESIAN_POINT('',(-102.874932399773,6.01759933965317,32.4581504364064));
#462=CARTESIAN_POINT('',(-102.688710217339,4.31557078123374,32.727933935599));
#463=CARTESIAN_POINT('',(-102.618107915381,3.45721186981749,32.8298045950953));
#464=CARTESIAN_POINT('',(-102.523754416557,1.73255866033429,32.9658357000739));
#465=CARTESIAN_POINT('',(-102.50000216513,0.866264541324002,32.999997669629));
#466=CARTESIAN_POINT('',(-102.5,0.,33.));
#467=B_SPLINE_CURVE_WITH_KNOTS('',3,(#297,#298,#299,#300,#301,#302,#303,#304,#305,#306,#307,
#308,#309,#310,#311,#312,#313,#314,#315,#316,#317,#318,#319,#320,#321,#322,#323,#324,#325,#326,
#327,#328,#329,#330,#331,#332,#333,#334,#335,#336,#337,#338,#339,#340,#341,#342,#343,#344,#345,
#346,#347,#348,#349,#350,#351,#352,#353,#354,#355,#356,#357,#358,#359,#360,#361,#362,#363,#364,
#365,#366,#367,#368,#369,#370,#371,#372,#373,#374,#375,#376,#377,#378,#379,#380,#381,#382,#383,
#384,#385,#386,#387,#388,#389,#390,#391,#392,#393,#394,#395,#396,#397,#398,#399,#400,#401,#402,
#403,#404,#405,#406,#407,#408,#409,#410,#411,#412,#413,#414,#415,#416,#417,#418,#419,#420,#421,
#422,#423,#424,#425,#426,#427,#428,#429,#430,#431,#432,#433,#434,#435,#436,#437,#438,#439,#440,
#441,#442,#443,#444,#445,#446,#447,#448,#449,#450,#451,#452,#453,#454,#455,#456,#457,#458,#459,
#460,#461,#462,#463,#464,#465,#466),.UNSPECIFIED.,.T.,.F.,(4,2,2,2,2,2,2,2,2,2,2,2,2,2,2,2,2,2,
2,2,2,2,2,2,2,2,2,2,2,2,2,2,2,2,2,2,2,2,2,2,2,2,2,2,2,2,2,2,2,2,2,2,2,2,2,2,2,2,2,2,2,2,2,2,2,2,
2,2,2,2,2,2,2,2,2,2,2,2,2,2,2,2,2,2,4),(0.,2.46454983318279,4.9289937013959,7.39421206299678,
9.85949002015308,12.3125740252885,14.7656390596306,17.2186894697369,19.6718604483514,
22.3403372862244,25.0089399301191,27.6812267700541,30.3536687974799,33.4891950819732,
36.6255173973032,39.7577086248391,42.8882660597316,45.0543340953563,47.2200507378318,
49.3821929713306,51.5443331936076,53.7184325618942,55.8925267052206,58.0679404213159,
60.2434006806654,62.2823684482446,64.3220890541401,66.3629002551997,68.4033915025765,
71.5042225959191,74.6062913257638,77.7138160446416,80.8209522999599,83.9624504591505,
87.1042366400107,90.2403684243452,93.3755582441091,95.8161275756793,98.2563597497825,
100.695363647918,103.134418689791,105.583032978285,108.031646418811,110.480244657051,
112.92876290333,115.225222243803,117.521566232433,119.818096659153,122.114755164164,
124.580106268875,127.045552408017,129.512268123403,131.979117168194,134.866143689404,
137.753594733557,140.643060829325,143.53216305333,146.107672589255,148.683215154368,
151.254612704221,153.82536421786,155.902765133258,157.979905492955,160.05494875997,
162.130018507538,164.206502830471,166.282974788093,168.362028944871,170.441360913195,
173.131000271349,175.821474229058,178.515108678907,181.208577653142,183.963723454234,
186.718862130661,189.474823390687,192.231055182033,195.451895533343,198.673231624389,
201.891012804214,205.107717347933,207.708183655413,210.308292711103,212.906206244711,
215.50406130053),.UNSPECIFIED.);
#468=CARTESIAN_POINT('',(-102.5,0.,33.));
#469=VERTEX_POINT('',#468);
#470=EDGE_CURVE('E48',#469,#469,#467,.T.);
#471=ORIENTED_EDGE('',*,*,#470,.T.);
#472=EDGE_LOOP('',(#471));
#473=FACE_BOUND('',#472,.T.);
#474=ADVANCED_FACE('F58',(#296,#473),#293,.F.);
#475=CARTESIAN_POINT('',(130.,0.,0.));
#476=DIRECTION('',(1.,0.,0.));
#477=DIRECTION('',(0.,0.,-1.));
#478=AXIS2_PLACEMENT_3D('',#475,#476,#477);
#479=PLANE('',#478);
#480=CARTESIAN_POINT('',(130.,0.,0.));
#481=DIRECTION('',(1.,0.,0.));
#482=DIRECTION('',(0.,0.,-1.));
#483=AXIS2_PLACEMENT_3D('',#480,#481,#482);
#484=CIRCLE('',#483,33.);
#485=CARTESIAN_POINT('',(130.,0.,-33.));
#486=VERTEX_POINT('',#485);
#487=EDGE_CURVE('E157',#486,#486,#484,.T.);
#488=ORIENTED_EDGE('',*,*,#487,.F.);
#489=EDGE_LOOP('',(#488));
#490=FACE_BOUND('',#489,.T.);
#491=ORIENTED_EDGE('',*,*,#245,.T.);
#492=EDGE_LOOP('',(#491));
#493=FACE_BOUND('',#492,.T.);
#494=ADVANCED_FACE('F68',(#490,#493),#479,.T.);
#495=CARTESIAN_POINT('',(-80.,0.,0.));
#496=DIRECTION('',(-1.,0.,0.));
#497=DIRECTION('',(0.,0.,1.));
#498=AXIS2_PLACEMENT_3D('',#495,#496,#497);
#499=CYLINDRICAL_SURFACE('',#498,33.);
#500=ORIENTED_EDGE('',*,*,#470,.F.);
#501=EDGE_LOOP('',(#500));
#502=FACE_BOUND('',#501,.T.);
#503=CARTESIAN_POINT('',(-80.,0.,0.));
#504=DIRECTION('',(1.,0.,0.));
#505=DIRECTION('',(0.,0.,-1.));
#506=AXIS2_PLACEMENT_3D('',#503,#504,#505);
#507=CIRCLE('',#506,33.);
#508=CARTESIAN_POINT('',(-80.,0.,-33.));
#509=VERTEX_POINT('',#508);
#510=EDGE_CURVE('E56',#509,#509,#507,.T.);
#511=ORIENTED_EDGE('',*,*,#510,.T.);
#512=EDGE_LOOP('',(#511));
#513=FACE_BOUND('',#512,.T.);
#514=ADVANCED_FACE('F62',(#502,#513),#499,.F.);
#515=CARTESIAN_POINT('',(-80.,0.,0.));
#516=DIRECTION('',(1.,0.,0.));
#517=DIRECTION('',(0.,0.,-1.));
#518=AXIS2_PLACEMENT_3D('',#515,#516,#517);
#519=PLANE('',#518);
#520=ORIENTED_EDGE('',*,*,#273,.T.);
#521=EDGE_LOOP('',(#520));
#522=FACE_BOUND('',#521,.T.);
#523=ORIENTED_EDGE('',*,*,#510,.F.);
#524=EDGE_LOOP('',(#523));
#525=FACE_BOUND('',#524,.T.);
#526=ADVANCED_FACE('F67',(#522,#525),#519,.F.);
#527=CARTESIAN_POINT('',(110.,0.,0.));
#528=DIRECTION('',(1.,0.,0.));
#529=DIRECTION('',(0.,0.,-1.));
#530=AXIS2_PLACEMENT_3D('',#527,#528,#529);
#531=CYLINDRICAL_SURFACE('',#530,33.);
#532=CARTESIAN_POINT('',(110.,0.,0.));
#533=DIRECTION('',(1.,0.,0.));
#534=DIRECTION('',(0.,0.,-1.));
#535=AXIS2_PLACEMENT_3D('',#532,#533,#534);
#536=CIRCLE('',#535,33.);
#537=CARTESIAN_POINT('',(110.,0.,-33.));
#538=VERTEX_POINT('',#537);
#539=EDGE_CURVE('E153',#538,#538,#536,.T.);
#540=ORIENTED_EDGE('',*,*,#539,.F.);
#541=EDGE_LOOP('',(#540));
#542=FACE_BOUND('',#541,.T.);
#543=ORIENTED_EDGE('',*,*,#487,.T.);
#544=EDGE_LOOP('',(#543));
#545=FACE_BOUND('',#544,.T.);
#546=ADVANCED_FACE('F306',(#542,#545),#531,.F.);
#547=CARTESIAN_POINT('',(110.,0.,0.));
#548=DIRECTION('',(1.,0.,0.));
#549=DIRECTION('',(0.,0.,-1.));
#550=AXIS2_PLACEMENT_3D('',#547,#548,#549);
#551=PLANE('',#550);
#552=ORIENTED_EDGE('',*,*,#284,.F.);
#553=EDGE_LOOP('',(#552));
#554=FACE_BOUND('',#553,.T.);
#555=ORIENTED_EDGE('',*,*,#539,.T.);
#556=EDGE_LOOP('',(#555));
#557=FACE_BOUND('',#556,.T.);
#558=ADVANCED_FACE('F254',(#554,#557),#551,.T.);
#559=CARTESIAN_POINT('',(29.7,0.,0.));
#560=DIRECTION('',(1.,0.,0.));
#561=DIRECTION('',(0.,0.,-1.));
#562=AXIS2_PLACEMENT_3D('',#559,#560,#561);
#563=CYLINDRICAL_SURFACE('',#562,38.0615);
#564=CARTESIAN_POINT('',(78.7262068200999,0.,0.));
#565=DIRECTION('',(-1.,0.,0.));
#566=DIRECTION('',(0.,0.,1.));
#567=AXIS2_PLACEMENT_3D('',#564,#565,#566);
#568=CIRCLE('',#567,38.0615);
#569=CARTESIAN_POINT('',(78.7262068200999,0.,38.0615));
#570=VERTEX_POINT('',#569);
#571=EDGE_CURVE('E147',#570,#570,#568,.F.);
#572=ORIENTED_EDGE('',*,*,#571,.F.);
#573=EDGE_LOOP('',(#572));
#574=FACE_BOUND('',#573,.T.);
#575=CARTESIAN_POINT('',(29.7,0.,0.));
#576=DIRECTION('',(1.,0.,0.));
#577=DIRECTION('',(0.,0.,-1.));
#578=AXIS2_PLACEMENT_3D('',#575,#576,#577);
#579=CIRCLE('',#578,38.0615);
#580=CARTESIAN_POINT('',(29.7,0.,-38.0615));
#581=VERTEX_POINT('',#580);
#582=EDGE_CURVE('E212',#581,#581,#579,.T.);
#583=ORIENTED_EDGE('',*,*,#582,.T.);
#584=EDGE_LOOP('',(#583));
#585=FACE_BOUND('',#584,.T.);
#586=ADVANCED_FACE('F218',(#574,#585),#563,.T.);
#587=CARTESIAN_POINT('',(29.7,0.,0.));
#588=DIRECTION('',(1.,0.,0.));
#589=DIRECTION('',(0.,0.,-1.));
#590=AXIS2_PLACEMENT_3D('',#587,#588,#589);
#591=PLANE('',#590);
#592=ORIENTED_EDGE('',*,*,#582,.F.);
#593=EDGE_LOOP('',(#592));
#594=FACE_BOUND('',#593,.T.);
#595=ORIENTED_EDGE('',*,*,#228,.T.);
#596=EDGE_LOOP('',(#595));
#597=FACE_BOUND('',#596,.T.);
#598=ADVANCED_FACE('F220',(#594,#597),#591,.T.);
#599=ORIENTED_EDGE('',*,*,#256,.F.);
#600=EDGE_LOOP('',(#599));
#601=FACE_BOUND('',#600,.T.);
#602=CARTESIAN_POINT('',(106.27380859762,0.,0.));
#603=DIRECTION('',(1.,0.,0.));
#604=DIRECTION('',(0.,0.,-1.));
#605=AXIS2_PLACEMENT_3D('',#602,#603,#604);
#606=CIRCLE('',#605,38.0615);
#607=CARTESIAN_POINT('',(106.27380859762,0.,-38.0615));
#608=VERTEX_POINT('',#607);
#609=EDGE_CURVE('E140',#608,#608,#606,.F.);
#610=ORIENTED_EDGE('',*,*,#609,.F.);
#611=EDGE_LOOP('',(#610));
#612=FACE_BOUND('',#611,.T.);
#613=ADVANCED_FACE('F85',(#601,#612),#563,.T.);
#614=CARTESIAN_POINT('',(80.9525154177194,0.,0.));
#615=DIRECTION('',(1.,0.,0.));
#616=DIRECTION('',(0.,0.,-1.));
#617=AXIS2_PLACEMENT_3D('',#614,#615,#616);
#618=TOROIDAL_SURFACE('',#617,37.043735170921,0.254000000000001);
#619=CARTESIAN_POINT('',(81.2065154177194,0.,0.));
#620=DIRECTION('',(1.,0.,0.));
#621=DIRECTION('',(0.,0.,-1.));
#622=AXIS2_PLACEMENT_3D('',#619,#620,#621);
#623=CIRCLE('',#622,37.043735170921);
#624=CARTESIAN_POINT('',(81.2065154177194,0.,-37.043735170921));
#625=VERTEX_POINT('',#624);
#626=EDGE_CURVE('E171',#625,#625,#623,.T.);
#627=ORIENTED_EDGE('',*,*,#626,.F.);
#628=EDGE_LOOP('',(#627));
#629=FACE_BOUND('',#628,.T.);
#630=CARTESIAN_POINT('',(80.9525154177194,0.,0.));
#631=DIRECTION('',(1.,0.,0.));
#632=DIRECTION('',(0.,0.,-1.));
#633=AXIS2_PLACEMENT_3D('',#630,#631,#632);
#634=CIRCLE('',#633,36.789735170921);
#635=CARTESIAN_POINT('',(80.9525154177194,0.,-36.789735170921));
#636=VERTEX_POINT('',#635);
#637=EDGE_CURVE('E168',#636,#636,#634,.T.);
#638=ORIENTED_EDGE('',*,*,#637,.T.);
#639=EDGE_LOOP('',(#638));
#640=FACE_BOUND('',#639,.T.);
#641=ADVANCED_FACE('F81',(#629,#640),#618,.F.);
#642=CARTESIAN_POINT('',(81.2065154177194,39.354735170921,0.));
#643=DIRECTION('',(1.,0.,0.));
#644=DIRECTION('',(0.,0.,-1.));
#645=AXIS2_PLACEMENT_3D('',#642,#643,#644);
#646=PLANE('',#645);
#647=CARTESIAN_POINT('',(81.2065154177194,0.,0.));
#648=DIRECTION('',(1.,0.,0.));
#649=DIRECTION('',(0.,0.,-1.));
#650=AXIS2_PLACEMENT_3D('',#647,#648,#649);
#651=CIRCLE('',#650,37.9222);
#652=CARTESIAN_POINT('',(81.2065154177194,0.,-37.9222));
#653=VERTEX_POINT('',#652);
#654=EDGE_CURVE('E39',#653,#653,#651,.F.);
#655=ORIENTED_EDGE('',*,*,#654,.T.);
#656=EDGE_LOOP('',(#655));
#657=FACE_BOUND('',#656,.T.);
#658=ORIENTED_EDGE('',*,*,#626,.T.);
#659=EDGE_LOOP('',(#658));
#660=FACE_BOUND('',#659,.T.);
#661=ADVANCED_FACE('F84',(#657,#660),#646,.F.);
#662=CARTESIAN_POINT('',(81.3843154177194,0.,0.));
#663=DIRECTION('',(1.,0.,0.));
#664=DIRECTION('',(0.,0.,-1.));
#665=AXIS2_PLACEMENT_3D('',#662,#663,#664);
#666=TOROIDAL_SURFACE('',#665,37.9222,0.1778);
#667=ORIENTED_EDGE('',*,*,#654,.F.);
#668=EDGE_LOOP('',(#667));
#669=FACE_BOUND('',#668,.T.);
#670=CARTESIAN_POINT('',(81.273824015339,0.,0.));
#671=DIRECTION('',(1.,0.,0.));
#672=DIRECTION('',(0.,0.,-1.));
#673=AXIS2_PLACEMENT_3D('',#670,#671,#672);
#674=CIRCLE('',#673,38.0615);
#675=CARTESIAN_POINT('',(81.273824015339,0.,-38.0615));
#676=VERTEX_POINT('',#675);
#677=EDGE_CURVE('E141',#676,#676,#674,.F.);
#678=ORIENTED_EDGE('',*,*,#677,.T.);
#679=EDGE_LOOP('',(#678));
#680=FACE_BOUND('',#679,.T.);
#681=ADVANCED_FACE('F79',(#669,#680),#666,.T.);
#682=CARTESIAN_POINT('',(130.,0.,0.));
#683=DIRECTION('',(1.,0.,0.));
#684=DIRECTION('',(0.,0.,-1.));
#685=AXIS2_PLACEMENT_3D('',#682,#683,#684);
#686=CYLINDRICAL_SURFACE('',#685,36.789735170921);
#687=ORIENTED_EDGE('',*,*,#637,.F.);
#688=EDGE_LOOP('',(#687));
#689=FACE_BOUND('',#688,.T.);
#690=CARTESIAN_POINT('',(79.0475154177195,0.,0.));
#691=DIRECTION('',(1.,0.,0.));
#692=DIRECTION('',(0.,0.,-1.));
#693=AXIS2_PLACEMENT_3D('',#690,#691,#692);
#694=CIRCLE('',#693,36.789735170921);
#695=CARTESIAN_POINT('',(79.0475154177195,0.,-36.789735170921));
#696=VERTEX_POINT('',#695);
#697=EDGE_CURVE('E165',#696,#696,#694,.T.);
#698=ORIENTED_EDGE('',*,*,#697,.T.);
#699=EDGE_LOOP('',(#698));
#700=FACE_BOUND('',#699,.T.);
#701=ADVANCED_FACE('F75',(#689,#700),#686,.T.);
#702=CARTESIAN_POINT('',(79.0475154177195,0.,0.));
#703=DIRECTION('',(1.,0.,0.));
#704=DIRECTION('',(0.,0.,-1.));
#705=AXIS2_PLACEMENT_3D('',#702,#703,#704);
#706=TOROIDAL_SURFACE('',#705,37.043735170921,0.254000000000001);
#707=ORIENTED_EDGE('',*,*,#697,.F.);
#708=EDGE_LOOP('',(#707));
#709=FACE_BOUND('',#708,.T.);
#710=CARTESIAN_POINT('',(78.7935154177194,0.,0.));
#711=DIRECTION('',(1.,0.,0.));
#712=DIRECTION('',(0.,0.,-1.));
#713=AXIS2_PLACEMENT_3D('',#710,#711,#712);
#714=CIRCLE('',#713,37.043735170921);
#715=CARTESIAN_POINT('',(78.7935154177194,0.,-37.043735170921));
#716=VERTEX_POINT('',#715);
#717=EDGE_CURVE('E162',#716,#716,#714,.T.);
#718=ORIENTED_EDGE('',*,*,#717,.T.);
#719=EDGE_LOOP('',(#718));
#720=FACE_BOUND('',#719,.T.);
#721=ADVANCED_FACE('F71',(#709,#720),#706,.F.);
#722=CARTESIAN_POINT('',(78.7935154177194,39.354735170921,0.));
#723=DIRECTION('',(-1.,0.,0.));
#724=DIRECTION('',(0.,0.,1.));
#725=AXIS2_PLACEMENT_3D('',#722,#723,#724);
#726=PLANE('',#725);
#727=CARTESIAN_POINT('',(78.7935154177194,0.,0.));
#728=DIRECTION('',(-1.,0.,0.));
#729=DIRECTION('',(0.,0.,1.));
#730=AXIS2_PLACEMENT_3D('',#727,#728,#729);
#731=CIRCLE('',#730,37.9222);
#732=CARTESIAN_POINT('',(78.7935154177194,0.,37.9222));
#733=VERTEX_POINT('',#732);
#734=EDGE_CURVE('E11',#733,#733,#731,.F.);
#735=ORIENTED_EDGE('',*,*,#734,.T.);
#736=EDGE_LOOP('',(#735));
#737=FACE_BOUND('',#736,.T.);
#738=ORIENTED_EDGE('',*,*,#717,.F.);
#739=EDGE_LOOP('',(#738));
#740=FACE_BOUND('',#739,.T.);
#741=ADVANCED_FACE('F74',(#737,#740),#726,.F.);
#742=CARTESIAN_POINT('',(78.6157154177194,0.,0.));
#743=DIRECTION('',(-1.,0.,0.));
#744=DIRECTION('',(0.,0.,1.));
#745=AXIS2_PLACEMENT_3D('',#742,#743,#744);
#746=TOROIDAL_SURFACE('',#745,37.9222,0.1778);
#747=ORIENTED_EDGE('',*,*,#734,.F.);
#748=EDGE_LOOP('',(#747));
#749=FACE_BOUND('',#748,.T.);
#750=ORIENTED_EDGE('',*,*,#571,.T.);
#751=EDGE_LOOP('',(#750));
#752=FACE_BOUND('',#751,.T.);
#753=ADVANCED_FACE('F33',(#749,#752),#746,.T.);
#754=CARTESIAN_POINT('',(103.72619140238,0.,0.));
#755=DIRECTION('',(-1.,0.,0.));
#756=DIRECTION('',(0.,0.,1.));
#757=AXIS2_PLACEMENT_3D('',#754,#755,#756);
#758=CIRCLE('',#757,38.0615);
#759=CARTESIAN_POINT('',(103.72619140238,0.,38.0615));
#760=VERTEX_POINT('',#759);
#761=EDGE_CURVE('E138',#760,#760,#758,.F.);
#762=ORIENTED_EDGE('',*,*,#761,.F.);
#763=EDGE_LOOP('',(#762));
#764=FACE_BOUND('',#763,.T.);
#765=ORIENTED_EDGE('',*,*,#677,.F.);
#766=EDGE_LOOP('',(#765));
#767=FACE_BOUND('',#766,.T.);
#768=ADVANCED_FACE('F106',(#764,#767),#563,.T.);
#769=CARTESIAN_POINT('',(105.9525,0.,0.));
#770=DIRECTION('',(1.,0.,0.));
#771=DIRECTION('',(0.,0.,-1.));
#772=AXIS2_PLACEMENT_3D('',#769,#770,#771);
#773=TOROIDAL_SURFACE('',#772,37.0715,0.254000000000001);
#774=CARTESIAN_POINT('',(106.2065,0.,0.));
#775=DIRECTION('',(1.,0.,0.));
#776=DIRECTION('',(0.,0.,-1.));
#777=AXIS2_PLACEMENT_3D('',#774,#775,#776);
#778=CIRCLE('',#777,37.0715);
#779=CARTESIAN_POINT('',(106.2065,0.,-37.0715));
#780=VERTEX_POINT('',#779);
#781=EDGE_CURVE('E123',#780,#780,#778,.T.);
#782=ORIENTED_EDGE('',*,*,#781,.F.);
#783=EDGE_LOOP('',(#782));
#784=FACE_BOUND('',#783,.T.);
#785=CARTESIAN_POINT('',(105.9525,0.,0.));
#786=DIRECTION('',(1.,0.,0.));
#787=DIRECTION('',(0.,0.,-1.));
#788=AXIS2_PLACEMENT_3D('',#785,#786,#787);
#789=CIRCLE('',#788,36.8175);
#790=CARTESIAN_POINT('',(105.9525,0.,-36.8175));
#791=VERTEX_POINT('',#790);
#792=EDGE_CURVE('E179',#791,#791,#789,.T.);
#793=ORIENTED_EDGE('',*,*,#792,.T.);
#794=EDGE_LOOP('',(#793));
#795=FACE_BOUND('',#794,.T.);
#796=ADVANCED_FACE('F102',(#784,#795),#773,.F.);
#797=CARTESIAN_POINT('',(106.2065,39.3825,0.));
#798=DIRECTION('',(1.,0.,0.));
#799=DIRECTION('',(0.,0.,-1.));
#800=AXIS2_PLACEMENT_3D('',#797,#798,#799);
#801=PLANE('',#800);
#802=CARTESIAN_POINT('',(106.2065,0.,0.));
#803=DIRECTION('',(1.,0.,0.));
#804=DIRECTION('',(0.,0.,-1.));
#805=AXIS2_PLACEMENT_3D('',#802,#803,#804);
#806=CIRCLE('',#805,37.9222);
#807=CARTESIAN_POINT('',(106.2065,0.,-37.9222));
#808=VERTEX_POINT('',#807);
#809=EDGE_CURVE('E127',#808,#808,#806,.F.);
#810=ORIENTED_EDGE('',*,*,#809,.T.);
#811=EDGE_LOOP('',(#810));
#812=FACE_BOUND('',#811,.T.);
#813=ORIENTED_EDGE('',*,*,#781,.T.);
#814=EDGE_LOOP('',(#813));
#815=FACE_BOUND('',#814,.T.);
#816=ADVANCED_FACE('F105',(#812,#815),#801,.F.);
#817=CARTESIAN_POINT('',(106.3843,0.,0.));
#818=DIRECTION('',(1.,0.,0.));
#819=DIRECTION('',(0.,0.,-1.));
#820=AXIS2_PLACEMENT_3D('',#817,#818,#819);
#821=TOROIDAL_SURFACE('',#820,37.9222,0.1778);
#822=ORIENTED_EDGE('',*,*,#809,.F.);
#823=EDGE_LOOP('',(#822));
#824=FACE_BOUND('',#823,.T.);
#825=ORIENTED_EDGE('',*,*,#609,.T.);
#826=EDGE_LOOP('',(#825));
#827=FACE_BOUND('',#826,.T.);
#828=ADVANCED_FACE('F100',(#824,#827),#821,.T.);
#829=CARTESIAN_POINT('',(130.,0.,0.));
#830=DIRECTION('',(1.,0.,0.));
#831=DIRECTION('',(0.,0.,-1.));
#832=AXIS2_PLACEMENT_3D('',#829,#830,#831);
#833=CYLINDRICAL_SURFACE('',#832,36.8175);
#834=ORIENTED_EDGE('',*,*,#792,.F.);
#835=EDGE_LOOP('',(#834));
#836=FACE_BOUND('',#835,.T.);
#837=CARTESIAN_POINT('',(104.0475,0.,0.));
#838=DIRECTION('',(1.,0.,0.));
#839=DIRECTION('',(0.,0.,-1.));
#840=AXIS2_PLACEMENT_3D('',#837,#838,#839);
#841=CIRCLE('',#840,36.8175);
#842=CARTESIAN_POINT('',(104.0475,0.,-36.8175));
#843=VERTEX_POINT('',#842);
#844=EDGE_CURVE('E177',#843,#843,#841,.T.);
#845=ORIENTED_EDGE('',*,*,#844,.T.);
#846=EDGE_LOOP('',(#845));
#847=FACE_BOUND('',#846,.T.);
#848=ADVANCED_FACE('F96',(#836,#847),#833,.T.);
#849=CARTESIAN_POINT('',(104.0475,0.,0.));
#850=DIRECTION('',(1.,0.,0.));
#851=DIRECTION('',(0.,0.,-1.));
#852=AXIS2_PLACEMENT_3D('',#849,#850,#851);
#853=TOROIDAL_SURFACE('',#852,37.0715,0.254000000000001);
#854=ORIENTED_EDGE('',*,*,#844,.F.);
#855=EDGE_LOOP('',(#854));
#856=FACE_BOUND('',#855,.T.);
#857=CARTESIAN_POINT('',(103.7935,0.,0.));
#858=DIRECTION('',(1.,0.,0.));
#859=DIRECTION('',(0.,0.,-1.));
#860=AXIS2_PLACEMENT_3D('',#857,#858,#859);
#861=CIRCLE('',#860,37.0715);
#862=CARTESIAN_POINT('',(103.7935,0.,-37.0715));
#863=VERTEX_POINT('',#862);
#864=EDGE_CURVE('E174',#863,#863,#861,.T.);
#865=ORIENTED_EDGE('',*,*,#864,.T.);
#866=EDGE_LOOP('',(#865));
#867=FACE_BOUND('',#866,.T.);
#868=ADVANCED_FACE('F92',(#856,#867),#853,.F.);
#869=CARTESIAN_POINT('',(103.7935,39.3825,0.));
#870=DIRECTION('',(-1.,0.,0.));
#871=DIRECTION('',(0.,0.,1.));
#872=AXIS2_PLACEMENT_3D('',#869,#870,#871);
#873=PLANE('',#872);
#874=CARTESIAN_POINT('',(103.7935,0.,0.));
#875=DIRECTION('',(-1.,0.,0.));
#876=DIRECTION('',(0.,0.,1.));
#877=AXIS2_PLACEMENT_3D('',#874,#875,#876);
#878=CIRCLE('',#877,37.9222);
#879=CARTESIAN_POINT('',(103.7935,0.,37.9222));
#880=VERTEX_POINT('',#879);
#881=EDGE_CURVE('E44',#880,#880,#878,.F.);
#882=ORIENTED_EDGE('',*,*,#881,.T.);
#883=EDGE_LOOP('',(#882));
#884=FACE_BOUND('',#883,.T.);
#885=ORIENTED_EDGE('',*,*,#864,.F.);
#886=EDGE_LOOP('',(#885));
#887=FACE_BOUND('',#886,.T.);
#888=ADVANCED_FACE('F95',(#884,#887),#873,.F.);
#889=CARTESIAN_POINT('',(103.6157,0.,0.));
#890=DIRECTION('',(-1.,0.,0.));
#891=DIRECTION('',(0.,0.,1.));
#892=AXIS2_PLACEMENT_3D('',#889,#890,#891);
#893=TOROIDAL_SURFACE('',#892,37.9222,0.1778);
#894=ORIENTED_EDGE('',*,*,#881,.F.);
#895=EDGE_LOOP('',(#894));
#896=FACE_BOUND('',#895,.T.);
#897=ORIENTED_EDGE('',*,*,#761,.T.);
#898=EDGE_LOOP('',(#897));
#899=FACE_BOUND('',#898,.T.);
#900=ADVANCED_FACE('F112',(#896,#899),#893,.T.);
#901=CLOSED_SHELL('',(#232,#260,#288,#474,#494,#514,#526,#546,#558,#586,#598,#613,#641,#661,
#681,#701,#721,#741,#753,#768,#796,#816,#828,#848,#868,#888,#900));
#902=MANIFOLD_SOLID_BREP('B2',#901);
#903=ADVANCED_BREP_SHAPE_REPRESENTATION('',(#18,#902),#14);
#904=SHAPE_DEFINITION_REPRESENTATION(#9,#903);
ENDSEC;
END-ISO-10303-21;
